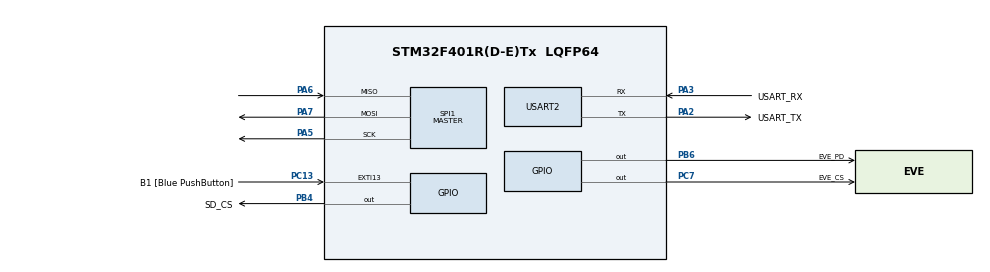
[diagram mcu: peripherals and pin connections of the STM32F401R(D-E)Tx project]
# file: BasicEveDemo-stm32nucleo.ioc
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Mcu.Family=STM32F4
Mcu.Name=STM32F401R(D-E)Tx
Mcu.Package=LQFP64
NVIC.PriorityGroup=NVIC_PRIORITYGROUP_0
PA13.GPIO_Label=TMS
PA13.Mode=Serial_Wire
PA13.Signal=SYS_JTMS-SWDIO
PA14.GPIO_Label=TCK
PA14.Mode=Serial_Wire
PA14.Signal=SYS_JTCK-SWCLK
PA2.GPIO_Label=USART_TX
PA2.GPIO_Mode=GPIO_MODE_AF_PP
PA2.GPIO_PuPd=GPIO_NOPULL
PA2.GPIO_Speed=GPIO_SPEED_FREQ_LOW
PA2.Mode=Asynchronous
PA2.Signal=USART2_TX
PA3.GPIO_Label=USART_RX
PA3.GPIO_Mode=GPIO_MODE_AF_PP
PA3.GPIO_PuPd=GPIO_NOPULL
PA3.GPIO_Speed=GPIO_SPEED_FREQ_LOW
PA3.Mode=Asynchronous
PA3.Signal=USART2_RX
PA5.Mode=Full_Duplex_Master
PA5.Signal=SPI1_SCK
PA6.Mode=Full_Duplex_Master
PA6.Signal=SPI1_MISO
PA7.Mode=Full_Duplex_Master
PA7.Signal=SPI1_MOSI
PB3.GPIO_Label=SWO
PB3.Signal=SYS_JTDO-SWO
PB4.GPIO_Label=SD_CS
PB4.PinState=GPIO_PIN_SET
PB4.Signal=GPIO_Output
PB6.GPIO_Label=EVE_PD
PB6.Signal=GPIO_Output
PC13-ANTI_TAMP.GPIO_Label=B1 [Blue PushButton]
PC13-ANTI_TAMP.GPIO_ModeDefaultEXTI=GPIO_MODE_IT_FALLING
PC13-ANTI_TAMP.GPIO_PuPd=GPIO_NOPULL
PC13-ANTI_TAMP.Signal=GPXTI13
PC14-OSC32_IN.Mode=LSE-External-Oscillator
PC14-OSC32_IN.Signal=RCC_OSC32_IN
PC15-OSC32_OUT.Mode=LSE-External-Oscillator
PC15-OSC32_OUT.Signal=RCC_OSC32_OUT
PC7.GPIO_Label=EVE_CS
PC7.PinState=GPIO_PIN_SET
PC7.Signal=GPIO_Output
PH0\ -\ OSC_IN.Mode=HSE-External-Clock-Source
PH0\ -\ OSC_IN.Signal=RCC_OSC_IN
PH1\ -\ OSC_OUT.Mode=HSE-External-Clock-Source
PH1\ -\ OSC_OUT.Signal=RCC_OSC_OUT
ProjectManager.HeapSize=0x200
ProjectManager.StackSize=0x400
ProjectManager.TargetToolchain=STM32CubeIDE
RCC.48MHZClocksFreq_Value=48000000
RCC.AHBFreq_Value=84000000
RCC.APB1CLKDivider=RCC_HCLK_DIV2
RCC.APB1Freq_Value=42000000
RCC.APB1TimFreq_Value=84000000
RCC.APB2Freq_Value=84000000
RCC.APB2TimFreq_Value=84000000
RCC.CortexFreq_Value=84000000
RCC.HCLKFreq_Value=84000000
RCC.HSE_VALUE=8000000
RCC.HSI_VALUE=16000000
RCC.PLLN=336
RCC.PLLP=RCC_PLLP_DIV4
RCC.PLLQ=7
RCC.SYSCLKFreq_VALUE=84000000
RCC.SYSCLKSource=RCC_SYSCLKSOURCE_PLLCLK
RCC.VCOOutputFreq_Value=336000000
SPI1.Direction=SPI_DIRECTION_2LINES
SPI1.Mode=SPI_MODE_MASTER
SPI1.VirtualType=VM_MASTER
USART2.VirtualMode=VM_ASYNC
board=NUCLEO-F401RE

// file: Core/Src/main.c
/* USER CODE BEGIN Header */
/**
  ******************************************************************************
  * @file           : main.c
  * @brief          : Main program body
  ******************************************************************************
  * @attention
  *
  * <h2><center>&copy; Copyright (c) 2020 STMicroelectronics.
  * All rights reserved.</center></h2>
  *
  * This software component is licensed by ST under BSD 3-Clause license,
  * the "License"; You may not use this file except in compliance with the
  * License. You may obtain a copy of the License at:
  *                        opensource.org/licenses/BSD-3-Clause
  *
  ******************************************************************************
  */
/* USER CODE END Header */

#include "main.h"

/* USER CODE BEGIN Includes */
#include "Eve2_81x.h"
#include "MatrixEve2Conf.h"
/* USER CODE END Includes */

SPI_HandleTypeDef hspi1;

UART_HandleTypeDef huart2;

void SystemClock_Config(void);
static void MX_GPIO_Init(void);
static void MX_USART2_UART_Init(void);
static void MX_SPI1_Init(void);

/* USER CODE BEGIN 0 */
//MakeScreen_MatrixOrbital draws a blue dot in the center screen, along
//with the text "MATRIX ORBITAL"
void MakeScreen_MatrixOrbital(uint8_t DotSize)
{
	Send_CMD(CMD_DLSTART);                  // Start a new display list
	Send_CMD(CLEAR_COLOR_RGB(0, 0, 0));     // Determine the clear screen color
	Send_CMD(CLEAR(1, 1, 1));	            // Clear the screen and the curren display list
	Send_CMD(TAG(1));                       // Tag the blue dot with a touch ID
	Send_CMD(COLOR_RGB(0, 0, 0));           // change colour to black
	Send_CMD(BEGIN(RECTS));                 // start drawing point
	Send_CMD(VERTEX2F(0,0));
	Send_CMD(VERTEX2F(Display_Width()*16,Display_Height()*16));
	Send_CMD(BEGIN(POINTS));                 // start drawing point
	Send_CMD(COLOR_RGB(26, 26, 192));        // change colour to blue
	Send_CMD(POINT_SIZE(DotSize * 16));      // set point size to DotSize pixels. Points = (pixels x 16)
	Send_CMD(VERTEX2II(Display_Width() / 2, Display_Height() / 2, 0, 0));     // place blue point
	Send_CMD(END());                         // end drawing point
	Send_CMD(COLOR_RGB(255, 255, 255));      //Change color to white for text
	Cmd_Text(Display_Width() / 2, Display_Height() / 2, 30, OPT_CENTER, " MATRIX         ORBITAL"); //Write text in the center of the screen
	Send_CMD(DISPLAY());                     //End the display list
	Send_CMD(CMD_SWAP);                      //Swap commands into RAM
	UpdateFIFO();                            // Trigger the CoProcessor to start processing the FIFO
}

// A calibration screen for the touch digitizer
void MakeScreen_Calibrate(void)
{
  Send_CMD(CMD_DLSTART);
  Send_CMD(CLEAR_COLOR_RGB(0,0,0));
  Send_CMD(CLEAR(1,1,1));
  Cmd_Text(100, 10, 27, OPT_CENTER, "Tap on the dots");
  Cmd_Calibrate(0);                                           // This widget generates a blocking screen that doesn't unblock until 3 dots have been touched
  Send_CMD(DISPLAY());
  Send_CMD(CMD_SWAP);
  UpdateFIFO();                                               // Trigger the CoProcessor to start processing commands out of the FIFO

  Wait4CoProFIFOEmpty();                                      // wait here until the coprocessor has read and executed every pending command.
}

/* USER CODE END 0 */

int main(void)
{

  /* MCU Configuration--------------------------------------------------------*/

  /* Reset of all peripherals, Initializes the Flash interface and the Systick. */
  HAL_Init();

  /* Configure the system clock */
  SystemClock_Config();

  /* Initialize all configured peripherals */
  MX_GPIO_Init();
  MX_USART2_UART_Init();
  MX_SPI1_Init();
  /* USER CODE BEGIN 2 */
  FT81x_Init(DISPLAY_50, BOARD_EVE2, TOUCH_TPC);
  MakeScreen_MatrixOrbital(20);
  if (Display_Touch() == TOUCH_TPC)
  {
	  MakeScreen_Calibrate();
  }
  int LastTag = 0;
  /* USER CODE END 2 */

  /* Infinite loop */
  while (1)
  {

    /* USER CODE BEGIN 3 */
	  //MakeScreen_MatrixOrbital(20 + rand() %50);
	  int Tag = rd8(REG_TOUCH_TAG + RAM_REG);                    // Check for touches
	  if (Tag != LastTag)
	  {
		  MakeScreen_MatrixOrbital(20 + (Tag ? 20 : 0));
		  LastTag = Tag;
	  }

  }
  /* USER CODE END 3 */
}

void SystemClock_Config(void)
{
  RCC_OscInitTypeDef RCC_OscInitStruct = {0};
  RCC_ClkInitTypeDef RCC_ClkInitStruct = {0};

  /** Configure the main internal regulator output voltage
  */
  __HAL_RCC_PWR_CLK_ENABLE();
  __HAL_PWR_VOLTAGESCALING_CONFIG(PWR_REGULATOR_VOLTAGE_SCALE2);
  /** Initializes the CPU, AHB and APB busses clocks
  */
  RCC_OscInitStruct.OscillatorType = RCC_OSCILLATORTYPE_HSI;
  RCC_OscInitStruct.HSIState = RCC_HSI_ON;
  RCC_OscInitStruct.HSICalibrationValue = RCC_HSICALIBRATION_DEFAULT;
  RCC_OscInitStruct.PLL.PLLState = RCC_PLL_ON;
  RCC_OscInitStruct.PLL.PLLSource = RCC_PLLSOURCE_HSI;
  RCC_OscInitStruct.PLL.PLLM = 16;
  RCC_OscInitStruct.PLL.PLLN = 336;
  RCC_OscInitStruct.PLL.PLLP = RCC_PLLP_DIV4;
  RCC_OscInitStruct.PLL.PLLQ = 7;
  if (HAL_RCC_OscConfig(&RCC_OscInitStruct) != HAL_OK)
  {
    Error_Handler();
  }
  /** Initializes the CPU, AHB and APB busses clocks
  */
  RCC_ClkInitStruct.ClockType = RCC_CLOCKTYPE_HCLK|RCC_CLOCKTYPE_SYSCLK
                              |RCC_CLOCKTYPE_PCLK1|RCC_CLOCKTYPE_PCLK2;
  RCC_ClkInitStruct.SYSCLKSource = RCC_SYSCLKSOURCE_PLLCLK;
  RCC_ClkInitStruct.AHBCLKDivider = RCC_SYSCLK_DIV2;
  RCC_ClkInitStruct.APB1CLKDivider = RCC_HCLK_DIV2;
  RCC_ClkInitStruct.APB2CLKDivider = RCC_HCLK_DIV1;

  if (HAL_RCC_ClockConfig(&RCC_ClkInitStruct, FLASH_LATENCY_1) != HAL_OK)
  {
    Error_Handler();
  }
}

static void MX_SPI1_Init(void)
{

  /* SPI1 parameter configuration*/
  hspi1.Instance = SPI1;
  hspi1.Init.Mode = SPI_MODE_MASTER;
  hspi1.Init.Direction = SPI_DIRECTION_2LINES;
  hspi1.Init.DataSize = SPI_DATASIZE_8BIT;
  hspi1.Init.CLKPolarity = SPI_POLARITY_LOW;
  hspi1.Init.CLKPhase = SPI_PHASE_1EDGE;
  hspi1.Init.NSS = SPI_NSS_SOFT;
  hspi1.Init.BaudRatePrescaler = SPI_BAUDRATEPRESCALER_32;
  hspi1.Init.FirstBit = SPI_FIRSTBIT_MSB;
  hspi1.Init.TIMode = SPI_TIMODE_DISABLE;
  hspi1.Init.CRCCalculation = SPI_CRCCALCULATION_DISABLE;
  hspi1.Init.CRCPolynomial = 10;
  if (HAL_SPI_Init(&hspi1) != HAL_OK)
  {
    Error_Handler();
  }

}

static void MX_USART2_UART_Init(void)
{

  huart2.Instance = USART2;
  huart2.Init.BaudRate = 115200;
  huart2.Init.WordLength = UART_WORDLENGTH_8B;
  huart2.Init.StopBits = UART_STOPBITS_1;
  huart2.Init.Parity = UART_PARITY_NONE;
  huart2.Init.Mode = UART_MODE_TX_RX;
  huart2.Init.HwFlowCtl = UART_HWCONTROL_NONE;
  huart2.Init.OverSampling = UART_OVERSAMPLING_16;
  if (HAL_UART_Init(&huart2) != HAL_OK)
  {
    Error_Handler();
  }

}

static void MX_GPIO_Init(void)
{
  GPIO_InitTypeDef GPIO_InitStruct = {0};

  /* GPIO Ports Clock Enable */
  __HAL_RCC_GPIOC_CLK_ENABLE();
  __HAL_RCC_GPIOH_CLK_ENABLE();
  __HAL_RCC_GPIOA_CLK_ENABLE();
  __HAL_RCC_GPIOB_CLK_ENABLE();

  /*Configure GPIO pin Output Level */
  HAL_GPIO_WritePin(EVE_CS_GPIO_Port, EVE_CS_Pin, GPIO_PIN_SET);

  /*Configure GPIO pin Output Level */
  HAL_GPIO_WritePin(SD_CS_GPIO_Port, SD_CS_Pin, GPIO_PIN_SET);

  /*Configure GPIO pin Output Level */
  HAL_GPIO_WritePin(EVE_PD_GPIO_Port, EVE_PD_Pin, GPIO_PIN_RESET);

  /*Configure GPIO pin : B1_Pin */
  GPIO_InitStruct.Pin = B1_Pin;
  GPIO_InitStruct.Mode = GPIO_MODE_IT_FALLING;
  GPIO_InitStruct.Pull = GPIO_NOPULL;
  HAL_GPIO_Init(B1_GPIO_Port, &GPIO_InitStruct);

  /*Configure GPIO pin : EVE_CS_Pin */
  GPIO_InitStruct.Pin = EVE_CS_Pin;
  GPIO_InitStruct.Mode = GPIO_MODE_OUTPUT_PP;
  GPIO_InitStruct.Pull = GPIO_NOPULL;
  GPIO_InitStruct.Speed = GPIO_SPEED_FREQ_VERY_HIGH;
  HAL_GPIO_Init(EVE_CS_GPIO_Port, &GPIO_InitStruct);

  /*Configure GPIO pin : SD_CS_Pin */
  GPIO_InitStruct.Pin = SD_CS_Pin;
  GPIO_InitStruct.Mode = GPIO_MODE_OUTPUT_PP;
  GPIO_InitStruct.Pull = GPIO_NOPULL;
  GPIO_InitStruct.Speed = GPIO_SPEED_FREQ_LOW;
  HAL_GPIO_Init(SD_CS_GPIO_Port, &GPIO_InitStruct);

  /*Configure GPIO pin : EVE_PD_Pin */
  GPIO_InitStruct.Pin = EVE_PD_Pin;
  GPIO_InitStruct.Mode = GPIO_MODE_OUTPUT_PP;
  GPIO_InitStruct.Pull = GPIO_NOPULL;
  GPIO_InitStruct.Speed = GPIO_SPEED_FREQ_VERY_HIGH;
  HAL_GPIO_Init(EVE_PD_GPIO_Port, &GPIO_InitStruct);

}

void Error_Handler(void)
{
}

/************************ (C) COPYRIGHT STMicroelectronics *****END OF FILE****/
